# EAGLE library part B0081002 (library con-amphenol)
AMPHENOL CONNECTOR

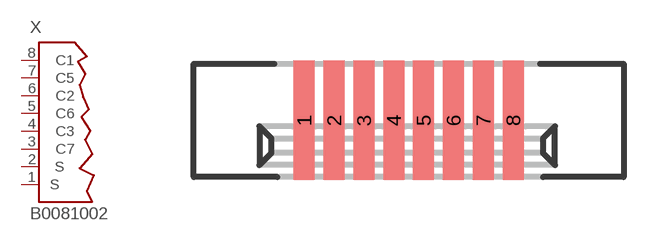
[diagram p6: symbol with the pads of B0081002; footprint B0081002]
Designator prefix X

## B0081002 (OC_FARNELL: unknown; OC_NEWARK: unknown)  [B0081002]
1  S1  pas
2  S2  pas
3  C7  pas
4  C3  pas
5  C6  pas
6  C2  pas
7  C5  pas
8  C1  pas

## Footprint B0081002 (pad centres in mm)
AMPHENOL CONNECTOR
smd 0.7 x 4: 1 -3.5,0; 2 -2.5,0; 3 -1.5,0; 4 -0.5,0; 5 0.5,0; 6 1.5,0; 7 2.5,0; 8 3.5,0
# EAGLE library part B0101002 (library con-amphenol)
AMPHENOL CONNECTOR

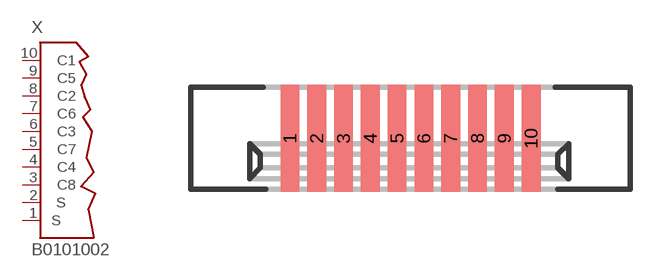
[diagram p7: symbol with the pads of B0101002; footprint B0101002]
Designator prefix X

## B0101002 (MF: AMPHENOL; MPN: C00710B0101002; OC_FARNELL: unknown; OC_NEWARK: 07C1377)  [B0101002]
1  S1  pas
2  S2  pas
3  C8  pas
4  C4  pas
5  C7  pas
6  C3  pas
7  C6  pas
8  C2  pas
9  C5  pas
10  C1  pas

## Footprint B0101002 (pad centres in mm)
AMPHENOL CONNECTOR
smd 0.7 x 4: 1 -4.5,0; 2 -3.5,0; 3 -2.5,0; 4 -1.5,0; 5 -0.5,0; 6 0.5,0; 7 1.5,0; 8 2.5,0; 9 3.5,0; 10 4.5,0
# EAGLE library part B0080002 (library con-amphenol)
AMPHENOL CONNECTOR

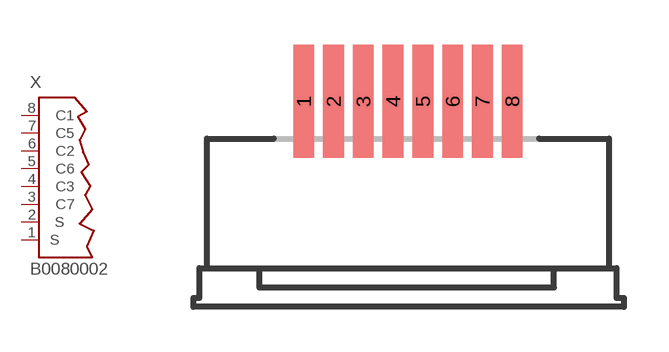
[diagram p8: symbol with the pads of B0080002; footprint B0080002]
Designator prefix X

## B0080002 (MF: AMPHENOL; MPN: C146 10B008 000 2; OC_FARNELL: unknown; OC_NEWARK: 03H9242)  [B0080002]
1  S1  pas
2  S2  pas
3  C7  pas
4  C3  pas
5  C6  pas
6  C2  pas
7  C5  pas
8  C1  pas

## Footprint B0080002 (pad centres in mm)
AMPHENOL CONNECTOR
smd 0.7 x 3.8: 1 -3.5,2.91; 2 -2.5,2.91; 3 -1.5,2.91; 4 -0.5,2.91; 5 0.5,2.91; 6 1.5,2.91; 7 2.5,2.91; 8 3.5,2.91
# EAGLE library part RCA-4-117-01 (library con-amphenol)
RCA JACK DIP R/A 4pos Source: RCA-4-117-01x.pdf

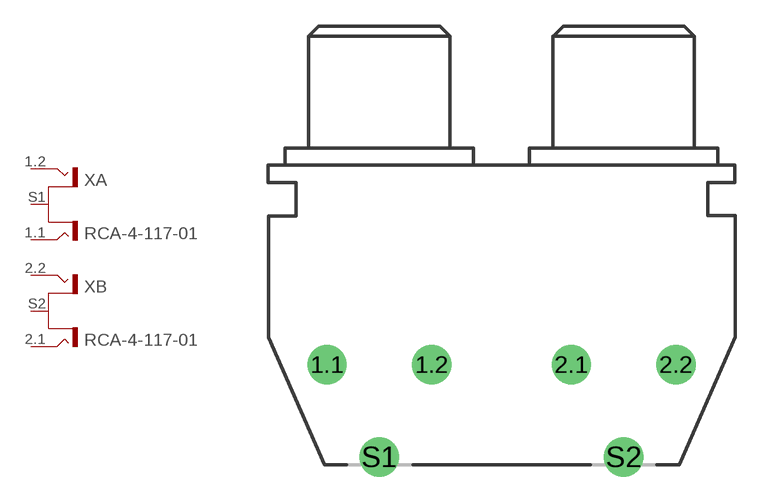
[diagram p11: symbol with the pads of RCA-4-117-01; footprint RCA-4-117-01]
Designator prefix X; gates A=CINCH2 B=CINCH2

## RCA-4-117-01  [RCA-4-117-01]
1.1  A:T1  pas
1.2  A:T2  pas
2.1  B:T1  pas
2.2  B:T2  pas
S1  A:S  pas
S2  B:S  pas

## Footprint RCA-4-117-01 (pad centres in mm)
RCA JACK DIP R/A 4pos Source: RCA-4-117-01x.pdf
drill 1.5 pad 2.184: 1.1 -10,0; 1.2 -4,0; 2.1 4,0; 2.2 10,0; S1 -7,-5.3; S2 7,-5.3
